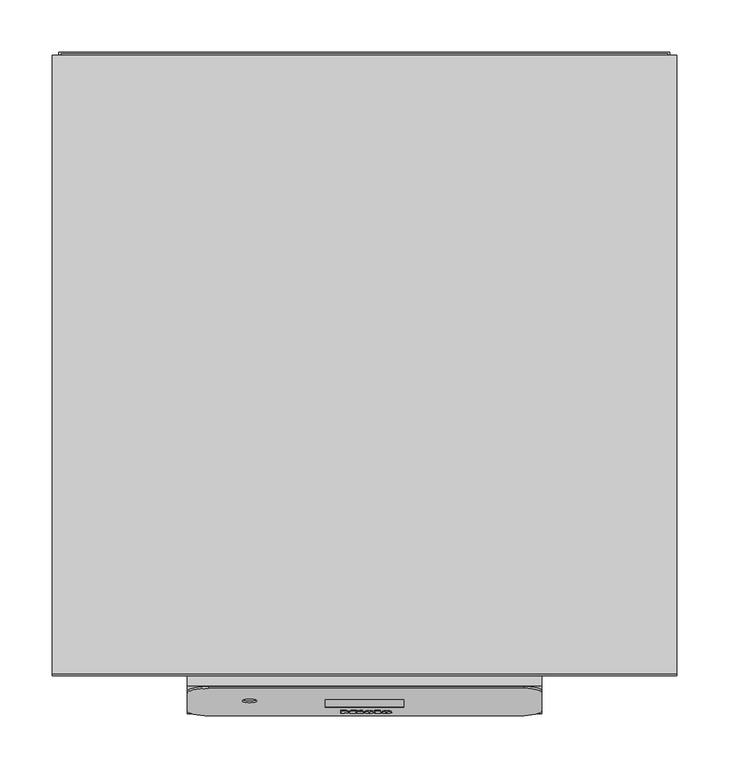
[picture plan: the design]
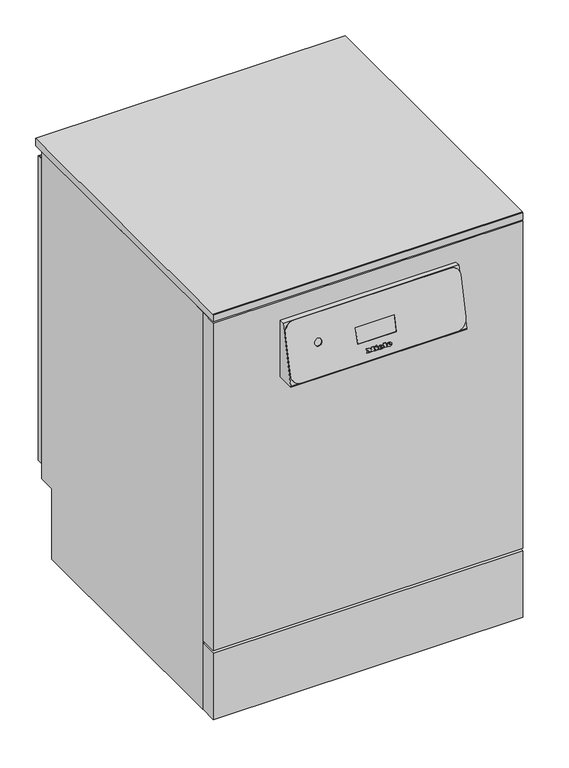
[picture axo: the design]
"""IFC4 building model written with IfcOpenShell, lengths in millimetres: proxy geometry."""

from ifc_helpers import new_model, si_unit, point, frame, frame_2d, origin, origin_with_axes, place, context, project, spatial, polyline, circle_curve, ellipse_curve, trimmed, segment, composite_curve, outline, extrude, faceted_brep, source, transform, mapped, element, save
from ifc_brep_helpers import plane_surface, cylinder_surface, revolved_surface, extruded_surface, advanced_brep


def specialty_equipment_f63f0287(model_context):
    return source(origin(), model_context, "Body", "SolidModel", [
        advanced_brep(
        [(20.656, -35.3539089, 679.552071), (20.656, -35.1721485, 680.339362), (26.008, -35.1721485, 680.339362), (16.696, -35.1721485, 680.339362), (18.896, -35.7804161, 677.7046654), (25.872, -35.3539089, 679.552071), (23.456, -35.3539089, 679.552071), (21.552, -35.5554651, 678.6790354), (20.656, -34.9417986, 681.337117), (20.656, -34.7456413, 682.1867677), (22.024, -34.7456413, 682.1867677), (22.024, -34.9417986, 681.337117), (20.656, -34.3795388, 679.3271199), (21.552, -34.581095, 678.4540844), (23.456, -34.3795388, 679.3271199), (25.872, -34.3795388, 679.3271199), (18.896, -34.806046, 677.4797143), (16.696, -34.1977784, 680.114411), (26.008, -34.1977784, 680.114411), (20.656, -34.1977784, 680.114411), (20.656, -33.9674285, 681.1121659), (22.024, -33.9674285, 681.1121659), (22.024, -33.7712712, 681.9618166), (20.656, -33.7712712, 681.9618166)],
        [
            (0, 1),
            (1, 2),
            (2, 3, ellipse_curve(frame((21.352, -35.1721485, 680.339362), z_axis=(0.0, -0.9743700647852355, 0.22495105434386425), x_axis=(-1.0, 0.0, 0.0)), 4.656, 3.848)),
            (3, 4, circle_curve(frame((19.7920436, -35.1109618, 680.6043907), z_axis=(0.0, -0.9743700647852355, 0.22495105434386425), x_axis=(0.0, -0.22495105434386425, -0.9743700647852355)), 3.1079688)),
            (4, 5, circle_curve(frame((21.2587936, -34.6358651, 682.6622603), z_axis=(0.0, -0.9743700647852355, 0.22495105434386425), x_axis=(0.0, -0.22495105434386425, -0.9743700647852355)), 5.6098607)),
            (5, 6),
            (6, 7, circle_curve(frame((21.9430588, -35.1865453, 680.2770023), z_axis=(0.0, 0.9743700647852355, -0.22495105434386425), x_axis=(0.0, -0.22495105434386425, -0.9743700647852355)), 1.6859795)),
            (7, 0, circle_curve(frame((21.552, -35.3539089, 679.552071), z_axis=(0.0, 0.9743700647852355, -0.22495105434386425), x_axis=(0.0, -0.22495105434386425, -0.9743700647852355)), 0.896)),
            (8, 9),
            (9, 10, circle_curve(frame((21.34, -34.7456413, 682.1867677), z_axis=(0.0, 0.9743700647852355, -0.22495105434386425), x_axis=(0.0, -0.22495105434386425, -0.9743700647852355)), 0.684)),
            (10, 11),
            (11, 8),
            (12, 13, circle_curve(frame((21.552, -34.3795388, 679.3271199), z_axis=(0.0, -0.9743700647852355, 0.22495105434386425), x_axis=(0.0, -0.22495105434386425, -0.9743700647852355)), 0.896)),
            (13, 14, circle_curve(frame((21.9430588, -34.2121753, 680.0520513), z_axis=(0.0, -0.9743700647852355, 0.22495105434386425), x_axis=(0.0, -0.22495105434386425, -0.9743700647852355)), 1.6859795)),
            (14, 15),
            (15, 16, circle_curve(frame((21.2587936, -33.6614951, 682.4373092), z_axis=(0.0, 0.9743700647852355, -0.22495105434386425), x_axis=(0.0, -0.22495105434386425, -0.9743700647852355)), 5.6098607)),
            (16, 17, circle_curve(frame((19.7920436, -34.1365917, 680.3794396), z_axis=(0.0, 0.9743700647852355, -0.22495105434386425), x_axis=(0.0, -0.22495105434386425, -0.9743700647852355)), 3.1079688)),
            (17, 18, ellipse_curve(frame((21.352, -34.1977784, 680.114411), z_axis=(0.0, 0.9743700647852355, -0.22495105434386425), x_axis=(-1.0, 0.0, 0.0)), 4.656, 3.848)),
            (18, 19),
            (19, 12),
            (20, 21),
            (21, 22),
            (22, 23, circle_curve(frame((21.34, -33.7712712, 681.9618166), z_axis=(0.0, -0.9743700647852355, 0.22495105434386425), x_axis=(0.0, -0.22495105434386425, -0.9743700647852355)), 0.684)),
            (23, 20),
            (0, 12),
            (19, 1),
            (18, 2),
            (5, 15),
            (14, 6),
            (17, 3),
            (13, 7),
            (16, 4),
            (8, 20),
            (23, 9),
            (22, 10),
            (21, 11),
        ],
        [
            plane_surface(frame((20.656, -35.1721485, 680.339362), z_axis=(0.0, -0.9743700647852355, 0.22495105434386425), x_axis=(0.0, 0.22495105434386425, 0.9743700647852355))),
            plane_surface(frame((20.656, -34.1977784, 680.114411), z_axis=(0.0, 0.9743700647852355, -0.22495105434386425), x_axis=(0.0, -0.22495105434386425, -0.9743700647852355))),
            plane_surface(frame((20.656, -35.3539089, 679.552071), z_axis=(1.0, 0.0, 0.0), x_axis=(0.0, 0.9743700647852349, -0.22495105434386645))),
            plane_surface(frame((20.656, -35.1721485, 680.339362), z_axis=(0.0, -0.22495105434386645, -0.9743700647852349), x_axis=(0.0, 0.9743700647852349, -0.22495105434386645))),
            plane_surface(frame((25.872, -35.3539089, 679.552071), z_axis=(0.0, 0.22495105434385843, 0.9743700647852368), x_axis=(0.0, 0.9743700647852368, -0.22495105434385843))),
            extruded_surface(trimmed(ellipse_curve(frame((21.352, -33.2234083, 679.8894599), z_axis=(0.0, -0.9743700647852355, 0.22495105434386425), x_axis=(-1.0, 0.0, 0.0)), 4.656, 3.848), [point((26.008, -33.2234083, 679.8894599))], [point((16.696, -33.2234083, 679.8894599))], True, "CARTESIAN"), (0.0, -0.9743700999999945, 0.2249510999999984), 1.0000000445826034),
            revolved_surface(polyline([(21.9430588, -34.59143807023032, 678.4092833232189), (21.9430588, -35.56580822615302, 678.6342343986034)]), (21.9430588, -34.2121753, 680.0520513), (0.0, 0.9743700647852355, -0.22495105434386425)),
            revolved_surface(polyline([(21.552, -34.581094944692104, 678.4540843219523), (21.552, -35.5554651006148, 678.679035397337)]), (21.552, -34.3795388, 679.3271199), (0.0, 0.9743700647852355, -0.22495105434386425)),
            cylinder_surface(frame((19.7920436, -34.1365917, 680.3794396), z_axis=(0.0, -0.9743700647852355, 0.22495105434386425), x_axis=(0.0, -0.22495105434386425, -0.9743700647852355)), 3.1079688),
            cylinder_surface(frame((21.2587936, -33.6614951, 682.4373092), z_axis=(0.0, -0.9743700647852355, 0.22495105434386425), x_axis=(0.0, -0.22495105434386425, -0.9743700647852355)), 5.6098607),
            plane_surface(frame((20.656, -34.9417986, 681.337117), z_axis=(1.0, 0.0, 0.0), x_axis=(0.0, 0.9743700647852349, -0.22495105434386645))),
            revolved_surface(polyline([(21.34, -33.925137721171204, 681.2953474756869), (21.34, -34.8995078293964, 681.5202985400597)]), (21.34, -33.7712712, 681.9618166), (0.0, 0.9743700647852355, -0.22495105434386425)),
            plane_surface(frame((22.024, -34.7456413, 682.1867677), z_axis=(-1.0, 0.0, 0.0), x_axis=(0.0, 0.9743700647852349, -0.22495105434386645))),
            plane_surface(frame((22.024, -34.9417986, 681.337117), z_axis=(0.0, 0.22495105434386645, 0.9743700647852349), x_axis=(0.0, 0.9743700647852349, -0.22495105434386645))),
        ],
        [
            (0, [[1, 2, 3, 4, 5, 6, 7, 8], [9, 10, 11, 12]]),
            (1, [[13, 14, 15, 16, 17, 18, 19, 20], [21, 22, 23, 24]]),
            (2, [[-1, 25, -20, 26]]),
            (3, [[-2, -26, -19, 27]]),
            (4, [[-6, 28, -15, 29]]),
            (5, [[-3, -27, -18, 30]]),
            (6, [[-7, -29, -14, 31]]),
            (7, [[-8, -31, -13, -25]]),
            (8, [[-4, -30, -17, 32]]),
            (9, [[-5, -32, -16, -28]]),
            (10, [[-9, 33, -24, 34]]),
            (11, [[-10, -34, -23, 35]]),
            (12, [[-11, -35, -22, 36]]),
            (13, [[-12, -36, -21, -33]]),
        ],
    ),
        advanced_brep(
        [(3.96, -35.3539089, 679.552071), (3.96, -35.1721485, 680.339362), (9.312, -35.1721485, 680.339362), (0.0, -35.1721485, 680.339362), (2.2, -35.7804161, 677.7046654), (9.176, -35.3539089, 679.552071), (6.76, -35.3539089, 679.552071), (4.856, -35.5554651, 678.6790354), (3.96, -34.9417986, 681.337117), (3.96, -34.7456413, 682.1867677), (5.328, -34.7456413, 682.1867677), (5.328, -34.9417986, 681.337117), (3.96, -34.3795388, 679.3271199), (4.856, -34.581095, 678.4540844), (6.76, -34.3795388, 679.3271199), (9.176, -34.3795388, 679.3271199), (2.2, -34.806046, 677.4797143), (0.0, -34.1977784, 680.114411), (9.312, -34.1977784, 680.114411), (3.96, -34.1977784, 680.114411), (3.96, -33.9674285, 681.1121659), (5.328, -33.9674285, 681.1121659), (5.328, -33.7712712, 681.9618166), (3.96, -33.7712712, 681.9618166)],
        [
            (0, 1),
            (1, 2),
            (2, 3, ellipse_curve(frame((4.656, -35.1721485, 680.339362), z_axis=(0.0, -0.9743700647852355, 0.22495105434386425), x_axis=(-1.0, 0.0, 0.0)), 4.656, 3.848)),
            (3, 4, circle_curve(frame((3.0960436, -35.1109618, 680.6043907), z_axis=(0.0, -0.9743700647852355, 0.22495105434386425), x_axis=(0.0, -0.22495105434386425, -0.9743700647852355)), 3.1079688)),
            (4, 5, circle_curve(frame((4.5627936, -34.6358651, 682.6622603), z_axis=(0.0, -0.9743700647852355, 0.22495105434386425), x_axis=(0.0, -0.22495105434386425, -0.9743700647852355)), 5.6098607)),
            (5, 6),
            (6, 7, circle_curve(frame((5.2470588, -35.1865453, 680.2770023), z_axis=(0.0, 0.9743700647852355, -0.22495105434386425), x_axis=(0.0, -0.22495105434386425, -0.9743700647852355)), 1.6859795)),
            (7, 0, circle_curve(frame((4.856, -35.3539089, 679.552071), z_axis=(0.0, 0.9743700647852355, -0.22495105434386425), x_axis=(0.0, -0.22495105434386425, -0.9743700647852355)), 0.896)),
            (8, 9),
            (9, 10, circle_curve(frame((4.644, -34.7456413, 682.1867677), z_axis=(0.0, 0.9743700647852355, -0.22495105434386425), x_axis=(0.0, -0.22495105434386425, -0.9743700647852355)), 0.684)),
            (10, 11),
            (11, 8),
            (12, 13, circle_curve(frame((4.856, -34.3795388, 679.3271199), z_axis=(0.0, -0.9743700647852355, 0.22495105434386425), x_axis=(0.0, -0.22495105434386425, -0.9743700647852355)), 0.896)),
            (13, 14, circle_curve(frame((5.2470588, -34.2121753, 680.0520513), z_axis=(0.0, -0.9743700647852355, 0.22495105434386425), x_axis=(0.0, -0.22495105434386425, -0.9743700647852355)), 1.6859795)),
            (14, 15),
            (15, 16, circle_curve(frame((4.5627936, -33.6614951, 682.4373092), z_axis=(0.0, 0.9743700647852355, -0.22495105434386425), x_axis=(0.0, -0.22495105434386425, -0.9743700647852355)), 5.6098607)),
            (16, 17, circle_curve(frame((3.0960436, -34.1365917, 680.3794396), z_axis=(0.0, 0.9743700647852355, -0.22495105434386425), x_axis=(0.0, -0.22495105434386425, -0.9743700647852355)), 3.1079688)),
            (17, 18, ellipse_curve(frame((4.656, -34.1977784, 680.114411), z_axis=(0.0, 0.9743700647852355, -0.22495105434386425), x_axis=(-1.0, 0.0, 0.0)), 4.656, 3.848)),
            (18, 19),
            (19, 12),
            (20, 21),
            (21, 22),
            (22, 23, circle_curve(frame((4.644, -33.7712712, 681.9618166), z_axis=(0.0, -0.9743700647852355, 0.22495105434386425), x_axis=(0.0, -0.22495105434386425, -0.9743700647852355)), 0.684)),
            (23, 20),
            (0, 12),
            (19, 1),
            (18, 2),
            (5, 15),
            (14, 6),
            (17, 3),
            (13, 7),
            (16, 4),
            (8, 20),
            (23, 9),
            (22, 10),
            (21, 11),
        ],
        [
            plane_surface(frame((3.96, -35.1721485, 680.339362), z_axis=(0.0, -0.9743700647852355, 0.22495105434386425), x_axis=(0.0, 0.22495105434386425, 0.9743700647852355))),
            plane_surface(frame((3.96, -34.1977784, 680.114411), z_axis=(0.0, 0.9743700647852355, -0.22495105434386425), x_axis=(0.0, -0.22495105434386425, -0.9743700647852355))),
            plane_surface(frame((3.96, -35.3539089, 679.552071), z_axis=(1.0, 0.0, 0.0), x_axis=(0.0, 0.9743700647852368, -0.22495105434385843))),
            plane_surface(frame((3.96, -35.1721485, 680.339362), z_axis=(0.0, -0.22495105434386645, -0.9743700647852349), x_axis=(0.0, 0.9743700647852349, -0.22495105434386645))),
            plane_surface(frame((9.176, -35.3539089, 679.552071), z_axis=(0.0, 0.22495105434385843, 0.9743700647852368), x_axis=(0.0, 0.9743700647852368, -0.22495105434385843))),
            extruded_surface(trimmed(ellipse_curve(frame((4.656, -33.2234083, 679.8894599), z_axis=(0.0, -0.9743700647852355, 0.22495105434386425), x_axis=(-1.0, 0.0, 0.0)), 4.656, 3.848), [point((9.312, -33.2234083, 679.8894599))], [point((0.0, -33.2234083, 679.8894599))], True, "CARTESIAN"), (0.0, -0.9743700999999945, 0.2249510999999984), 1.0000000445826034),
            revolved_surface(polyline([(5.2470588, -34.59143807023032, 678.4092833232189), (5.2470588, -35.56580822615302, 678.6342343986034)]), (5.2470588, -34.2121753, 680.0520513), (0.0, 0.9743700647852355, -0.22495105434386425)),
            revolved_surface(polyline([(4.856, -34.581094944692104, 678.4540843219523), (4.856, -35.5554651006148, 678.679035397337)]), (4.856, -34.3795388, 679.3271199), (0.0, 0.9743700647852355, -0.22495105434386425)),
            cylinder_surface(frame((3.0960436, -34.1365917, 680.3794396), z_axis=(0.0, -0.9743700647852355, 0.22495105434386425), x_axis=(0.0, -0.22495105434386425, -0.9743700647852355)), 3.1079688),
            cylinder_surface(frame((4.5627936, -33.6614951, 682.4373092), z_axis=(0.0, -0.9743700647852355, 0.22495105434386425), x_axis=(0.0, -0.22495105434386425, -0.9743700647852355)), 5.6098607),
            plane_surface(frame((3.96, -34.9417986, 681.337117), z_axis=(1.0, 0.0, 0.0), x_axis=(0.0, 0.9743700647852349, -0.22495105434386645))),
            revolved_surface(polyline([(4.644, -33.925137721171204, 681.2953474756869), (4.644, -34.8995078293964, 681.5202985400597)]), (4.644, -33.7712712, 681.9618166), (0.0, 0.9743700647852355, -0.22495105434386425)),
            plane_surface(frame((5.328, -34.7456413, 682.1867677), z_axis=(-1.0, 0.0, 0.0), x_axis=(0.0, 0.9743700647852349, -0.22495105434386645))),
            plane_surface(frame((5.328, -34.9417986, 681.337117), z_axis=(0.0, 0.22495105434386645, 0.9743700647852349), x_axis=(0.0, 0.9743700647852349, -0.22495105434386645))),
        ],
        [
            (0, [[1, 2, 3, 4, 5, 6, 7, 8], [9, 10, 11, 12]]),
            (1, [[13, 14, 15, 16, 17, 18, 19, 20], [21, 22, 23, 24]]),
            (2, [[-1, 25, -20, 26]]),
            (3, [[-2, -26, -19, 27]]),
            (4, [[-6, 28, -15, 29]]),
            (5, [[-3, -27, -18, 30]]),
            (6, [[-7, -29, -14, 31]]),
            (7, [[-8, -31, -13, -25]]),
            (8, [[-4, -30, -17, 32]]),
            (9, [[-5, -32, -16, -28]]),
            (10, [[-9, 33, -24, 34]]),
            (11, [[-10, -34, -23, 35]]),
            (12, [[-11, -35, -22, 36]]),
            (13, [[-12, -36, -21, -33]]),
        ],
    ),
        extrude(outline(polyline([(0.0, 0.0), (-0.0109087, -2.9993294), (-1.4390415, -2.9920868), (-1.4315307, 0.0), (0.0, 0.0)])), frame((-4.784, -33.1126145, 684.8147722), z_axis=(0.0, -0.9743700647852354, 0.22495105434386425), x_axis=(-0.42472021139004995, 0.20365373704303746, 0.8821212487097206)), (0.0, 0.0, 1.0), 1.0),
        extrude(outline(polyline([(-0.4933908, 2.4141097), (-2.7800844, -2.4601583), (-7.0459742, -0.4588767), (-7.4401146, -1.2990179), (-8.6568709, -0.728194), (-5.9760369, 4.9862153), (-4.7592806, 4.4153913), (-5.1636142, 3.5535222), (-2.1941494, 2.16044), (-1.7898157, 3.022309), (-0.4933908, 2.4141097)])), frame((-4.784, -33.1126145, 684.8147722), z_axis=(0.0, -0.9743700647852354, 0.22495105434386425), x_axis=(-0.42472021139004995, 0.20365373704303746, 0.8821212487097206)), (0.0, 0.0, 1.0), 1.0),
        extrude(outline(polyline([(0.0, 0.0), (0.0, -1.3039999), (-5.504, -1.3039999), (-5.504, 5.352), (-6.488, 5.352), (-6.488, 6.696), (0.0, 6.696), (0.0, 5.352), (-0.96, 5.352), (-0.96, 0.0), (0.0, 0.0)])), frame((9.76, -33.2997738, 684.0040963), z_axis=(0.0, -0.9743700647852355, 0.22495105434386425), x_axis=(-1.0, 0.0, 0.0)), (0.0, 0.0, 1.0), 1.0),
        extrude(outline(polyline([(0.0, 0.0), (0.0, -1.3039999), (-5.576, -1.3039999), (-7.92, 1.6960001), (-10.256, -1.3039999), (-15.128, -1.3039999), (-15.128, 0.0), (-14.112, 0.0), (-14.112, 5.352), (-15.128, 5.352), (-15.128, 6.696), (-8.744, 6.696), (-8.744, 5.352), (-9.728, 5.352), (-9.728, 1.8807777), (-6.136, 6.696), (-2.56, 1.9488752), (-2.56, 5.352), (-3.52, 5.352), (-3.52, 6.696), (0.0, 6.696), (0.0, 5.352), (-0.968, 5.352), (-0.968, 0.0), (0.0, 0.0)])), frame((-22.704, -33.2997738, 684.0040963), z_axis=(0.0, -0.9743700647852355, 0.22495105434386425), x_axis=(-1.0, 0.0, 0.0)), (0.0, 0.0, 1.0), 1.0),
        extrude(outline(polyline([(1.7745866, 832.3), (594.2, 832.3), (594.2, 817.0), (0.2, 817.0), (0.2, 830.7254134), (1.7745866, 832.3)])), frame((-299.0, 0.0, 0.0), z_axis=(1.0, 0.0, 0.0), x_axis=(0.0, 1.0, 0.0)), (0.0, 0.0, 1.0), 598.0),
        extrude(outline(polyline([(-0.1038681, 775.5857792), (-0.1038681, 660.0), (-36.1981904, 660.0), (-36.1981904, 662.5588517), (-10.1038681, 775.5857792), (-0.1038681, 775.5857792)])), frame((-169.8831565, 0.0, 0.0), z_axis=(1.0, 0.0, 0.0), x_axis=(0.0, 1.0, 0.0)), (0.0, 0.0, 1.0), 339.766313),
        extrude(outline(polyline([(299.0, 34.0), (299.0, 0.0), (-299.0, 0.0), (-299.0, 34.0), (299.0, 34.0)])), frame((0.0, 0.0, 4.5), z_axis=(0.0, 0.0, 1.0), x_axis=(1.0, 0.0, 0.0)), (0.0, 0.0, 1.0), 135.5),
        extrude(outline(polyline([(299.0, 34.0), (299.0, 0.0), (-299.0, 0.0), (-299.0, 34.0), (299.0, 34.0)])), frame((0.0, 0.0, 145.0), z_axis=(0.0, 0.0, 1.0), x_axis=(1.0, 0.0, 0.0)), (0.0, 0.0, 1.0), 670.0),
        advanced_brep(
        [(153.3281651, -12.0526082, 776.0356813), (-148.8831565, -12.0526082, 776.0356813), (-169.8831565, -16.7765804, 755.57391), (-169.8831565, -33.4229584, 683.4705252), (-148.8831565, -38.1469305, 663.0087538), (148.8831565, -38.1469305, 663.0087538), (169.8831565, -33.4229584, 683.4705252), (169.8831565, -15.776671, 759.9049933), (-102.8831565, -24.0088923, 724.2473253), (-116.8831565, -24.0088923, 724.2473253), (37.5, -23.1425191, 728.0), (37.5, -30.0685648, 698.0), (-37.5, -30.0685648, 698.0), (-37.5, -23.1425191, 728.0), (148.8831565, -36.1981904, 662.5588517), (169.8831565, -31.4742182, 683.0206231), (169.8831565, -13.8279308, 759.4550912), (153.3281651, -10.1038681, 775.5857792), (-148.8831565, -36.1981904, 662.5588517), (-169.8831565, -31.4742182, 683.0206231), (-169.8831565, -14.8278402, 755.1240079), (-148.8831565, -10.1038681, 775.5857792), (37.5, -28.0159566, 698.0), (37.5, -21.0899109, 728.0), (-37.5, -21.0899109, 728.0), (-37.5, -28.0159566, 698.0), (-116.8831565, -22.4281396, 723.8823798), (-102.8831565, -22.4281396, 723.8823798)],
        [
            (0, 1),
            (1, 2, circle_curve(frame((-148.8831565, -16.7765804, 755.57391), z_axis=(0.0, -0.9743700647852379, 0.22495105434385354), x_axis=(1.0, 0.0, 0.0)), 21.0)),
            (2, 3),
            (3, 4, circle_curve(frame((-148.8831565, -33.4229584, 683.4705252), z_axis=(0.0, -0.9743700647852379, 0.22495105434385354), x_axis=(1.0, 0.0, 0.0)), 21.0)),
            (4, 5),
            (5, 6, circle_curve(frame((148.8831565, -33.4229584, 683.4705252), z_axis=(0.0, -0.9743700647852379, 0.22495105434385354), x_axis=(1.0, 0.0, 0.0)), 21.0)),
            (6, 7),
            (7, 0, circle_curve(frame((153.3281651, -15.776671, 759.9049933), z_axis=(0.0, -0.9743700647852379, 0.22495105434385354), x_axis=(1.0, 0.0, 0.0)), 16.5549913)),
            (8, 9, circle_curve(frame((-109.8831565, -24.0088923, 724.2473253), z_axis=(0.0, 0.9743700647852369, -0.22495105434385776), x_axis=(1.0, 0.0, 0.0)), 7.0)),
            (9, 8, circle_curve(frame((-109.8831565, -24.0088923, 724.2473253), z_axis=(0.0, 0.9743700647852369, -0.22495105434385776), x_axis=(1.0, 0.0, 0.0)), 7.0)),
            (10, 11),
            (11, 12),
            (12, 13),
            (13, 10),
            (5, 14),
            (14, 15, circle_curve(frame((148.8831565, -31.4742182, 683.0206231), z_axis=(0.0, -0.9743700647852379, 0.22495105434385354), x_axis=(1.0, 0.0, 0.0)), 21.0)),
            (15, 6),
            (15, 16),
            (16, 7),
            (16, 17, circle_curve(frame((153.3281651, -13.8279308, 759.4550912), z_axis=(0.0, -0.9743700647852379, 0.22495105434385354), x_axis=(1.0, 0.0, 0.0)), 16.5549913)),
            (17, 0),
            (14, 18),
            (18, 19, circle_curve(frame((-148.8831565, -31.4742182, 683.0206231), z_axis=(0.0, 0.9743700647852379, -0.22495105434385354), x_axis=(1.0, 0.0, 0.0)), 21.0)),
            (19, 20),
            (20, 21, circle_curve(frame((-148.8831565, -14.8278402, 755.1240079), z_axis=(0.0, 0.9743700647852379, -0.22495105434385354), x_axis=(1.0, 0.0, 0.0)), 21.0)),
            (21, 17),
            (22, 23),
            (23, 24),
            (24, 25),
            (25, 22),
            (21, 1),
            (20, 2),
            (19, 3),
            (18, 4),
            (26, 27, circle_curve(frame((-109.8831565, -22.4281396, 723.8823798), z_axis=(0.0, -0.9743700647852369, 0.22495105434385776), x_axis=(1.0, 0.0, 0.0)), 7.0)),
            (27, 26, circle_curve(frame((-109.8831565, -22.4281396, 723.8823798), z_axis=(0.0, -0.9743700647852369, 0.22495105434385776), x_axis=(1.0, 0.0, 0.0)), 7.0)),
            (26, 9),
            (8, 27),
            (11, 22),
            (25, 12),
            (23, 10),
            (13, 24),
        ],
        [
            plane_surface(frame((-166.8819453, -12.0526082, 776.0356813), z_axis=(0.0, -0.9743700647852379, 0.22495105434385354), x_axis=(-1.0, 0.0, 0.0))),
            cylinder_surface(frame((148.8831565, -31.4742182, 683.0206231), z_axis=(0.0, -0.9743700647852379, 0.22495105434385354), x_axis=(1.0, 0.0, 0.0)), 21.0),
            plane_surface(frame((169.8831565, -33.4229584, 683.4705252), z_axis=(1.0000000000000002, 0.0, 0.0), x_axis=(0.0, 0.9743700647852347, -0.22495105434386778))),
            cylinder_surface(frame((153.3281651, -13.8279308, 759.4550912), z_axis=(0.0, -0.9743700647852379, 0.22495105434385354), x_axis=(1.0, 0.0, 0.0)), 16.5549913),
            plane_surface(frame((-166.8819453, -10.1038681, 775.5857792), z_axis=(0.0, 0.9743700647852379, -0.22495105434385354), x_axis=(1.0, 0.0, 0.0))),
            plane_surface(frame((153.3281651, -12.0526082, 776.0356813), z_axis=(0.0, 0.22495105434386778, 0.9743700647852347), x_axis=(0.0, 0.9743700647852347, -0.22495105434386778))),
            cylinder_surface(frame((-148.8831565, -14.8278402, 755.1240079), z_axis=(0.0, -0.9743700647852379, 0.22495105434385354), x_axis=(1.0, 0.0, 0.0)), 21.0),
            plane_surface(frame((-169.8831565, -16.7765804, 755.57391), z_axis=(-1.0, 0.0, 0.0), x_axis=(0.0, 0.9743700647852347, -0.22495105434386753))),
            cylinder_surface(frame((-148.8831565, -31.4742182, 683.0206231), z_axis=(0.0, -0.9743700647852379, 0.22495105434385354), x_axis=(1.0, 0.0, 0.0)), 21.0),
            plane_surface(frame((-148.8831565, -38.1469305, 663.0087538), z_axis=(0.0, -0.22495105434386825, -0.9743700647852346), x_axis=(0.0, 0.9743700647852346, -0.22495105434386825))),
            plane_surface(frame((-102.8831565, -22.4281396, 723.8823798), z_axis=(0.0, -0.9743700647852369, 0.2249510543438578), x_axis=(0.0, -0.2249510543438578, -0.9743700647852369))),
            revolved_surface(polyline([(-102.8831565, -24.008892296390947, 724.2473253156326), (-102.8831565, -22.4281396, 723.8823798)]), (-109.8831565, -22.4281396, 723.8823798), (0.0, -0.9743700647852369, 0.22495105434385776)),
            plane_surface(frame((37.5, -30.0685648, 698.0), z_axis=(0.0, 0.0, 1.0), x_axis=(-1.0, 0.0, 0.0))),
            plane_surface(frame((37.5, -21.0899109, 728.0), z_axis=(0.0, 0.0, -1.0), x_axis=(-1.0, 0.0, 0.0))),
            plane_surface(frame((37.5, -23.1425191, 728.0), z_axis=(-1.0000000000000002, 0.0, 0.0), x_axis=(0.0, -0.22495105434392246, -0.974370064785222))),
            plane_surface(frame((-37.5, -23.1425191, 728.0), z_axis=(1.0000000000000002, 0.0, 0.0), x_axis=(0.0, 0.22495105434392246, 0.974370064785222))),
        ],
        [
            (0, [[1, 2, 3, 4, 5, 6, 7, 8], [9, 10], [11, 12, 13, 14]]),
            (1, [[-6, 15, 16, 17]]),
            (2, [[-7, -17, 18, 19]]),
            (3, [[-8, -19, 20, 21]]),
            (4, [[-20, -18, -16, 22, 23, 24, 25, 26], [27, 28, 29, 30]]),
            (5, [[-1, -21, -26, 31]]),
            (6, [[-2, -31, -25, 32]]),
            (7, [[-3, -32, -24, 33]]),
            (8, [[-4, -33, -23, 34]]),
            (9, [[-5, -34, -22, -15]]),
            (10, [[35, 36]]),
            (11, [[-35, 37, -9, 38]]),
            (11, [[-36, -38, -10, -37]]),
            (12, [[39, -30, 40, -12]]),
            (13, [[41, -14, 42, -28]]),
            (14, [[-41, -27, -39, -11]]),
            (15, [[-40, -29, -42, -13]]),
        ],
    ),
        extrude(outline(polyline([(-23.1425191, 728.0), (-21.0899109, 728.0), (-28.0159566, 698.0), (-30.0685648, 698.0), (-23.1425191, 728.0)])), frame((-37.5, 0.0, 0.0), z_axis=(1.0, 0.0, 0.0), x_axis=(0.0, 1.0, 0.0)), (0.0, 0.0, 1.0), 75.0),
        extrude(outline(polyline([(35.0, 817.0), (575.0, 817.0), (575.0, 148.0), (541.0, 148.0), (541.0, 4.2000122), (35.0, 4.2000122), (35.0, 817.0)])), frame((-299.0, 0.0, 0.0), z_axis=(1.0, 0.0, 0.0), x_axis=(0.0, 1.0, 0.0)), (0.0, 0.0, 1.0), 598.0),
        extrude(outline(polyline([(-172.0947306, 541.0), (-252.9150967, 541.0), (-252.9150967, 546.8796322), (-172.0947306, 546.8796322), (-172.0947306, 541.0)])), frame((0.0, 0.0, 83.2113443), z_axis=(0.0, 0.0, 1.0), x_axis=(1.0, 0.0, 0.0)), (0.0, 0.0, 1.0), 9.5402229),
        extrude(outline(polyline([(-172.0947306, 541.0), (-252.9150967, 541.0), (-252.9150967, 546.8796322), (-172.0947306, 546.8796322), (-172.0947306, 541.0)])), frame((0.0, 0.0, 67.2113431), z_axis=(0.0, 0.0, 1.0), x_axis=(1.0, 0.0, 0.0)), (0.0, 0.0, 1.0), 9.5826234),
        extrude(outline(polyline([(-172.0947306, 541.0), (-252.9150967, 541.0), (-252.9150967, 546.8796322), (-172.0947306, 546.8796322), (-172.0947306, 541.0)])), frame((0.0, 0.0, 49.1113767), z_axis=(0.0, 0.0, 1.0), x_axis=(1.0, 0.0, 0.0)), (0.0, 0.0, 1.0), 11.5700235),
        faceted_brep([(292.4999939, 597.3069992, 792.0057337), (-292.5000061, 597.3069992, 792.0057337), (-292.5000061, 575.0, 792.0057337), (-291.0000061, 575.0, 792.0057337), (-291.0000061, 596.3069992, 792.0057337), (290.9999949, 596.3069992, 792.0057337), (290.9999949, 575.0, 792.0057337), (292.4999939, 575.0, 792.0057337), (292.4999939, 597.3069992, 170.291519), (292.4999939, 575.0, 170.291519), (290.9999949, 575.0, 170.291519), (290.9999949, 596.3069992, 170.291519), (-291.0000061, 596.3069992, 170.291519), (-291.0000061, 575.0, 170.291519), (-292.5000061, 575.0, 170.291519), (-292.5000061, 597.3069992, 170.291519), (-200.000102, 597.3069992, 319.6113699), (-200.000102, 597.3069992, 244.365213), (-125.000102, 597.3069992, 244.365213), (-125.000102, 597.3069992, 319.6113699), (-200.000102, 596.3069992, 244.365213), (-200.000102, 596.3069992, 319.6113699), (-125.000102, 596.3069992, 319.6113699), (-125.000102, 596.3069992, 244.365213)], [[[0, 1, 2, 3, 4, 5, 6, 7]], [[8, 9, 10, 11, 12, 13, 14, 15]], [[1, 0, 8, 15], [16, 17, 18, 19]], [[2, 1, 15, 14]], [[3, 2, 14, 13]], [[4, 3, 13, 12]], [[5, 4, 12, 11], [20, 21, 22, 23]], [[6, 5, 11, 10]], [[7, 6, 10, 9]], [[0, 7, 9, 8]], [[20, 17, 16, 21]], [[17, 20, 23, 18]], [[18, 23, 22, 19]], [[21, 16, 19, 22]]]),
        extrude(outline(polyline([(70.6242327, 186.565003), (80.6698637, 186.565003), (80.6698637, 179.3447057), (79.4141598, 179.3447057), (79.4141598, 185.3092991), (76.4318631, 185.3092991), (76.4318631, 179.6586317), (75.1761592, 179.6586317), (75.1761592, 185.3092991), (71.8799366, 185.3092991), (71.8799366, 179.1877427), (70.6242327, 179.1877427), (70.6242327, 186.565003)])), frame((0.0, 571.0, 0.0), z_axis=(0.0, 1.0, 0.0), x_axis=(0.0, 0.0, 1.0)), (0.0, 0.0, 1.0), 1.0),
        extrude(outline(polyline([(70.6242327, 177.3041869), (80.6698637, 177.3041869), (80.6698637, 176.048483), (71.8799366, 176.048483), (71.8799366, 171.0256675), (70.6242327, 171.0256675), (70.6242327, 177.3041869)])), frame((0.0, 571.0, 0.0), z_axis=(0.0, 1.0, 0.0), x_axis=(0.0, 0.0, 1.0)), (0.0, 0.0, 1.0), 1.0),
        extrude(outline(polyline([(46.0, 96.7862239), (56.045631, 92.7763102), (56.045631, 91.7069998), (46.0, 87.6970861), (46.0, 89.0239138), (49.1392597, 90.1741582), (49.1392597, 94.3116044), (46.0, 95.4593962), (46.0, 96.7862239)]), holes=[polyline([(50.3949636, 93.8505256), (50.3949636, 90.6327844), (52.864678, 91.5377741), (54.7899271, 92.241655), (53.0805021, 92.8670544), (50.3949636, 93.8505256)])]), frame((0.0, 571.0, 0.0), z_axis=(0.0, 1.0, 0.0), x_axis=(0.0, 0.0, 1.0)), (0.0, 0.0, 1.0), 1.0),
        extrude(outline(polyline([(46.0, 84.5578264), (56.045631, 87.297321), (56.045631, 86.0023764), (49.4433755, 84.4131261), (47.4053092, 83.9226168), (49.207931, 83.3977718), (56.045631, 81.406304), (56.045631, 79.539916), (51.0890343, 78.0929135), (47.4053092, 77.0162455), (49.3845144, 76.5404514), (56.045631, 74.936486), (56.045631, 73.6415413), (46.0, 76.3834885), (46.0, 77.7250315), (53.7500474, 80.1334323), (54.8316204, 80.4694312), (53.5293182, 80.8471233), (46.0, 83.0421526), (46.0, 84.5578264)])), frame((0.0, 571.0, 0.0), z_axis=(0.0, 1.0, 0.0), x_axis=(0.0, 0.0, 1.0)), (0.0, 0.0, 1.0), 1.0),
        extrude(outline(composite_curve([segment(trimmed(circle_curve(frame_2d((51.0, 85.0998392)), 8.0), [point((51.0, 77.0998392))], [point((51.0, 93.0998392))], False, "CARTESIAN"), True, "CONTINUOUS"), segment(trimmed(circle_curve(frame_2d((51.0, 85.0998392)), 8.0), [point((51.0, 93.0998392))], [point((51.0, 77.0998392))], False, "CARTESIAN"), True, "CONTINUOUS")], self_intersect=False)), frame((0.0, 541.0, 0.0), z_axis=(0.0, 1.0, 0.0), x_axis=(0.0, 0.0, 1.0)), (0.0, 0.0, 1.0), 30.0),
        extrude(outline(polyline([(94.6239875, 133.557834), (104.6696185, 136.2973286), (104.6696185, 135.002384), (98.067363, 133.4131338), (96.0292967, 132.9226244), (97.8319185, 132.3977795), (104.6696185, 130.4063116), (104.6696185, 128.5399236), (99.7130218, 127.0929211), (96.0292967, 126.0162531), (98.0085019, 125.5404591), (104.6696185, 123.9364936), (104.6696185, 122.641549), (94.6239875, 125.3834961), (94.6239875, 126.7250391), (102.3740349, 129.1334399), (103.4556079, 129.4694388), (102.1533057, 129.847131), (94.6239875, 132.0421602), (94.6239875, 133.557834)])), frame((0.0, 571.0, 0.0), z_axis=(0.0, 1.0, 0.0), x_axis=(0.0, 0.0, 1.0)), (0.0, 0.0, 1.0), 1.0),
        extrude(outline(polyline([(94.6239875, 144.6163668), (104.6696185, 144.6163668), (104.6696185, 143.3606629), (99.7522625, 143.3606629), (104.6696185, 138.210315), (104.6696185, 136.4542916), (100.53953, 140.7781313), (94.6239875, 136.2973286), (94.6239875, 137.8326228), (99.6909489, 141.6684057), (98.0771732, 143.3606629), (94.6239875, 143.3606629), (94.6239875, 144.6163668)])), frame((0.0, 571.0, 0.0), z_axis=(0.0, 1.0, 0.0), x_axis=(0.0, 0.0, 1.0)), (0.0, 0.0, 1.0), 1.0),
        extrude(outline(polyline([(118.1398187, 18.2077062), (128.1854497, 18.2077062), (128.1854497, 14.7422578), (128.0407495, 12.9494462), (127.3221533, 11.4730132), (125.6053707, 10.283528), (123.2165903, 9.888668), (121.1895605, 10.1559956), (119.7266164, 10.8427087), (118.8154953, 11.7599611), (118.311497, 12.9604827), (118.1398187, 14.5754846), (118.1398187, 18.2077062)]), holes=[polyline([(119.3955226, 16.9520023), (119.3955226, 14.7299951), (119.5770111, 13.1137669), (120.0895933, 12.1817991), (121.3367133, 11.4178309), (123.2362106, 11.1443719), (125.6151809, 11.6802533), (126.728637, 12.9837819), (126.9297459, 14.7643307), (126.9297459, 16.9520023), (119.3955226, 16.9520023)])]), frame((0.0, 571.0, 0.0), z_axis=(0.0, 1.0, 0.0), x_axis=(0.0, 0.0, 1.0)), (0.0, 0.0, 1.0), 1.0),
        extrude(outline(polyline([(121.5930044, 8.6329642), (121.5930044, 7.3772603), (120.3360742, 6.9725901), (119.5414491, 5.9842138), (119.2385596, 4.4783502), (119.4678727, 3.1662377), (120.0981772, 2.3188828), (120.940627, 2.0405188), (121.7242156, 2.2489853), (122.2944327, 3.1024715), (122.7739056, 4.930845), (123.3931736, 6.8990137), (124.3275939, 7.9670977), (125.5759401, 8.3190382), (126.9971909, 7.8837112), (128.0002825, 6.6120657), (128.3424127, 4.7505828), (127.9843409, 2.7640201), (126.9321984, 1.4396449), (125.360116, 0.9417779), (125.360116, 2.1974818), (126.6501555, 2.9087203), (127.0867088, 4.7015319), (126.6550606, 6.4992486), (125.6127283, 7.0633343), (124.7420743, 6.6635692), (124.0406459, 4.6132402), (123.4103414, 2.391233), (122.3925346, 1.1759961), (120.9725101, 0.7848149), (119.4703253, 1.2348572), (118.3740369, 2.5298019), (117.9828557, 4.4292992), (118.4046938, 6.6721531), (119.6751129, 8.0909513), (121.5930044, 8.6329642)])), frame((0.0, 571.0, 0.0), z_axis=(0.0, 1.0, 0.0), x_axis=(0.0, 0.0, 1.0)), (0.0, 0.0, 1.0), 1.0),
        extrude(outline(composite_curve([segment(trimmed(circle_curve(frame_2d((126.8499756, 10.1811127)), 2.9851521), [point((126.8499756, 7.1959606))], [point((126.8499756, 13.1662647))], False, "CARTESIAN"), True, "CONTINUOUS"), segment(trimmed(circle_curve(frame_2d((126.8499756, 10.1811127)), 2.9851521), [point((126.8499756, 13.1662647))], [point((126.8499756, 7.1959606))], False, "CARTESIAN"), True, "CONTINUOUS")], self_intersect=False)), frame((0.0, 541.0, 0.0), z_axis=(0.0, 1.0, 0.0), x_axis=(0.0, 0.0, 1.0)), (0.0, 0.0, 1.0), 30.0),
        extrude(outline(composite_curve([segment(trimmed(circle_curve(frame_2d((117.0999756, 10.1811127)), 3.0), [point((117.0999756, 7.1811127))], [point((117.0999756, 13.1811127))], False, "CARTESIAN"), True, "CONTINUOUS"), segment(trimmed(circle_curve(frame_2d((117.0999756, 10.1811127)), 3.0), [point((117.0999756, 13.1811127))], [point((117.0999756, 7.1811127))], False, "CARTESIAN"), True, "CONTINUOUS")], self_intersect=False)), frame((0.0, 541.0, 0.0), z_axis=(0.0, 1.0, 0.0), x_axis=(0.0, 0.0, 1.0)), (0.0, 0.0, 1.0), 30.0),
        extrude(outline(composite_curve([segment(trimmed(circle_curve(frame_2d((107.3499443, 10.1811127)), 3.0), [point((107.3499443, 7.1811127))], [point((107.3499443, 13.1811127))], False, "CARTESIAN"), True, "CONTINUOUS"), segment(trimmed(circle_curve(frame_2d((107.3499443, 10.1811127)), 3.0), [point((107.3499443, 13.1811127))], [point((107.3499443, 7.1811127))], False, "CARTESIAN"), True, "CONTINUOUS")], self_intersect=False)), frame((0.0, 541.0, 0.0), z_axis=(0.0, 1.0, 0.0), x_axis=(0.0, 0.0, 1.0)), (0.0, 0.0, 1.0), 30.0),
        extrude(outline(composite_curve([segment(trimmed(circle_curve(frame_2d((136.5999756, 10.1811127)), 3.0), [point((136.5999756, 7.1811127))], [point((136.5999756, 13.1811127))], False, "CARTESIAN"), True, "CONTINUOUS"), segment(trimmed(circle_curve(frame_2d((136.5999756, 10.1811127)), 3.0), [point((136.5999756, 13.1811127))], [point((136.5999756, 7.1811127))], False, "CARTESIAN"), True, "CONTINUOUS")], self_intersect=False)), frame((0.0, 541.0, 0.0), z_axis=(0.0, 1.0, 0.0), x_axis=(0.0, 0.0, 1.0)), (0.0, 0.0, 1.0), 30.0),
        extrude(outline(polyline([(99.6239875, 19.6811122), (148.0, 19.6811122), (148.0, 1.1811127), (99.6239875, 1.1811127), (99.6239875, 19.6811122)]), holes=[polyline([(100.6239875, 18.6811122), (100.6239875, 2.1811127), (147.0, 2.1811127), (147.0, 18.6811122), (100.6239875, 18.6811122)])]), frame((0.0, 541.0, 0.0), z_axis=(0.0, 1.0, 0.0), x_axis=(0.0, 0.0, 1.0)), (0.0, 0.0, 1.0), 1.0),
        extrude(outline(polyline([(41.5900269, 145.1730949), (51.6356579, 147.9125895), (51.6356579, 146.6176449), (45.0334023, 145.0283946), (42.9953361, 144.5378853), (44.7979579, 144.0130403), (51.6356579, 142.0215725), (51.6356579, 140.1551845), (46.6790611, 138.708182), (42.9953361, 137.631514), (44.9745412, 137.1557199), (51.6356579, 135.5517544), (51.6356579, 134.2568098), (41.5900269, 136.998757), (41.5900269, 138.3403), (49.3400742, 140.7487008), (50.4216473, 141.0846996), (49.119345, 141.4623918), (41.5900269, 143.6574211), (41.5900269, 145.1730949)])), frame((0.0, 571.0, 0.0), z_axis=(0.0, 1.0, 0.0), x_axis=(0.0, 0.0, 1.0)), (0.0, 0.0, 1.0), 1.0),
        extrude(outline(polyline([(41.5900269, 131.2033893), (51.6356579, 133.9428838), (51.6356579, 132.6479392), (45.0334023, 131.058689), (42.9953361, 130.5681797), (44.7979579, 130.0433347), (51.6356579, 128.0518668), (51.6356579, 126.1854788), (46.6790611, 124.7384763), (42.9953361, 123.6618084), (44.9745412, 123.1860143), (51.6356579, 121.5820488), (51.6356579, 120.2871042), (41.5900269, 123.0290513), (41.5900269, 124.3705943), (49.3400742, 126.7789951), (50.4216473, 127.114994), (49.119345, 127.4926862), (41.5900269, 129.6877154), (41.5900269, 131.2033893)])), frame((0.0, 571.0, 0.0), z_axis=(0.0, 1.0, 0.0), x_axis=(0.0, 0.0, 1.0)), (0.0, 0.0, 1.0), 1.0),
        extrude(outline(composite_curve([segment(trimmed(circle_curve(frame_2d((46.5900269, 134.0998468)), 8.0), [point((46.5900269, 126.0998468))], [point((46.5900269, 142.0998468))], False, "CARTESIAN"), True, "CONTINUOUS"), segment(trimmed(circle_curve(frame_2d((46.5900269, 134.0998468)), 8.0), [point((46.5900269, 142.0998468))], [point((46.5900269, 126.0998468))], False, "CARTESIAN"), True, "CONTINUOUS")], self_intersect=False)), frame((0.0, 541.0, 0.0), z_axis=(0.0, 1.0, 0.0), x_axis=(0.0, 0.0, 1.0)), (0.0, 0.0, 1.0), 30.0),
        extrude(outline(polyline([(118.1398187, -7.1235653), (128.1854497, -7.1235653), (128.1854497, -10.5890137), (128.0407495, -12.3818253), (127.3221533, -13.8582584), (125.6053707, -15.0477435), (123.2165903, -15.4426035), (121.1895605, -15.1752759), (119.7266164, -14.4885629), (118.8154953, -13.5713104), (118.311497, -12.3707889), (118.1398187, -10.7557869), (118.1398187, -7.1235653)]), holes=[polyline([(119.3955226, -8.3792692), (119.3955226, -10.6012765), (119.5770111, -12.2175047), (120.0895933, -13.1494724), (121.3367133, -13.9134407), (123.2362106, -14.1868996), (125.6151809, -13.6510182), (126.728637, -12.3474897), (126.9297459, -10.5669408), (126.9297459, -8.3792692), (119.3955226, -8.3792692)])]), frame((0.0, 571.0, 0.0), z_axis=(0.0, 1.0, 0.0), x_axis=(0.0, 0.0, 1.0)), (0.0, 0.0, 1.0), 1.0),
        extrude(outline(polyline([(121.5930044, -16.6983074), (121.5930044, -17.9540113), (120.3360742, -18.3586815), (119.5414491, -19.3470578), (119.2385596, -20.8529214), (119.4678727, -22.1650338), (120.0981772, -23.0123887), (120.940627, -23.2907528), (121.7242156, -23.0822863), (122.2944327, -22.2288001), (122.7739056, -20.4004265), (123.3931736, -18.4322579), (124.3275939, -17.3641738), (125.5759401, -17.0122334), (126.9971909, -17.4475604), (128.0002825, -18.7192058), (128.3424127, -20.5806887), (127.9843409, -22.5672515), (126.9321984, -23.8916267), (125.360116, -24.3894936), (125.360116, -23.1337898), (126.6501555, -22.4225512), (127.0867088, -20.6297397), (126.6550606, -18.832023), (125.6127283, -18.2679372), (124.7420743, -18.6677023), (124.0406459, -20.7180313), (123.4103414, -22.9400386), (122.3925346, -24.1552754), (120.9725101, -24.5464566), (119.4703253, -24.0964143), (118.3740369, -22.8014697), (117.9828557, -20.9019723), (118.4046938, -18.6591184), (119.6751129, -17.2403202), (121.5930044, -16.6983074)])), frame((0.0, 571.0, 0.0), z_axis=(0.0, 1.0, 0.0), x_axis=(0.0, 0.0, 1.0)), (0.0, 0.0, 1.0), 1.0),
        extrude(outline(composite_curve([segment(trimmed(circle_curve(frame_2d((126.8499756, -15.1501589)), 2.9851521), [point((126.8499756, -18.135311))], [point((126.8499756, -12.1650068))], False, "CARTESIAN"), True, "CONTINUOUS"), segment(trimmed(circle_curve(frame_2d((126.8499756, -15.1501589)), 2.9851521), [point((126.8499756, -12.1650068))], [point((126.8499756, -18.135311))], False, "CARTESIAN"), True, "CONTINUOUS")], self_intersect=False)), frame((0.0, 541.0, 0.0), z_axis=(0.0, 1.0, 0.0), x_axis=(0.0, 0.0, 1.0)), (0.0, 0.0, 1.0), 30.0),
        extrude(outline(composite_curve([segment(trimmed(circle_curve(frame_2d((117.0999756, -15.1501589)), 3.0), [point((117.0999756, -18.1501589))], [point((117.0999756, -12.1501589))], False, "CARTESIAN"), True, "CONTINUOUS"), segment(trimmed(circle_curve(frame_2d((117.0999756, -15.1501589)), 3.0), [point((117.0999756, -12.1501589))], [point((117.0999756, -18.1501589))], False, "CARTESIAN"), True, "CONTINUOUS")], self_intersect=False)), frame((0.0, 541.0, 0.0), z_axis=(0.0, 1.0, 0.0), x_axis=(0.0, 0.0, 1.0)), (0.0, 0.0, 1.0), 30.0),
        extrude(outline(composite_curve([segment(trimmed(circle_curve(frame_2d((107.3499443, -15.1501589)), 3.0), [point((107.3499443, -18.1501589))], [point((107.3499443, -12.1501589))], False, "CARTESIAN"), True, "CONTINUOUS"), segment(trimmed(circle_curve(frame_2d((107.3499443, -15.1501589)), 3.0), [point((107.3499443, -12.1501589))], [point((107.3499443, -18.1501589))], False, "CARTESIAN"), True, "CONTINUOUS")], self_intersect=False)), frame((0.0, 541.0, 0.0), z_axis=(0.0, 1.0, 0.0), x_axis=(0.0, 0.0, 1.0)), (0.0, 0.0, 1.0), 30.0),
        extrude(outline(composite_curve([segment(trimmed(circle_curve(frame_2d((136.5999756, -15.1501589)), 3.0), [point((136.5999756, -18.1501589))], [point((136.5999756, -12.1501589))], False, "CARTESIAN"), True, "CONTINUOUS"), segment(trimmed(circle_curve(frame_2d((136.5999756, -15.1501589)), 3.0), [point((136.5999756, -12.1501589))], [point((136.5999756, -18.1501589))], False, "CARTESIAN"), True, "CONTINUOUS")], self_intersect=False)), frame((0.0, 541.0, 0.0), z_axis=(0.0, 1.0, 0.0), x_axis=(0.0, 0.0, 1.0)), (0.0, 0.0, 1.0), 30.0),
        extrude(outline(polyline([(99.6239875, -5.6501594), (148.0, -5.6501594), (148.0, -24.1501589), (99.6239875, -24.1501589), (99.6239875, -5.6501594)]), holes=[polyline([(100.6239875, -6.6501594), (100.6239875, -23.1501589), (147.0, -23.1501589), (147.0, -6.6501594), (100.6239875, -6.6501594)])]), frame((0.0, 541.0, 0.0), z_axis=(0.0, 1.0, 0.0), x_axis=(0.0, 0.0, 1.0)), (0.0, 0.0, 1.0), 1.0),
        extrude(outline(polyline([(294.0108337, -153.1353281), (304.0564648, -153.1353281), (304.0564648, -156.6007765), (303.9117645, -158.3935881), (303.1931683, -159.8700212), (301.4763857, -161.0595063), (299.0876053, -161.4543663), (297.0605755, -161.1870387), (295.5976314, -160.5003256), (294.6865103, -159.5830732), (294.182512, -158.3825516), (294.0108337, -156.7675497), (294.0108337, -153.1353281)]), holes=[polyline([(295.2665376, -154.391032), (295.2665376, -156.6130392), (295.4480261, -158.2292675), (295.9606083, -159.1612352), (297.2077283, -159.9252035), (299.1072256, -160.1986624), (301.4861959, -159.662781), (302.5996521, -158.3592524), (302.8007609, -156.5787036), (302.8007609, -154.391032), (295.2665376, -154.391032)])]), frame((0.0, 585.0, 0.0), z_axis=(0.0, 1.0, 0.0), x_axis=(0.0, 0.0, 1.0)), (0.0, 0.0, 1.0), 1.0),
        extrude(outline(polyline([(297.4640194, -162.7100702), (297.4640194, -163.965774), (296.2070893, -164.3704442), (295.4124641, -165.3588205), (295.1095746, -166.8646842), (295.3388877, -168.1767966), (295.9691922, -169.0241515), (296.811642, -169.3025155), (297.5952306, -169.094049), (298.1654477, -168.2405628), (298.6449206, -166.4121893), (299.2641886, -164.4440206), (300.1986089, -163.3759366), (301.4469551, -163.0239961), (302.8682059, -163.4593232), (303.8712975, -164.7309686), (304.2134277, -166.5924515), (303.8553559, -168.5790143), (302.8032134, -169.9033894), (301.231131, -170.4012564), (301.231131, -169.1455525), (302.5211706, -168.434314), (302.9577239, -166.6415024), (302.5260757, -164.8437857), (301.4837433, -164.2797), (300.6130893, -164.6794651), (299.9116609, -166.7297941), (299.2813565, -168.9518013), (298.2635496, -170.1670382), (296.8435251, -170.5582194), (295.3413403, -170.1081771), (294.2450519, -168.8132325), (293.8538708, -166.9137351), (294.2757088, -164.6708812), (295.5461279, -163.252083), (297.4640194, -162.7100702)])), frame((0.0, 585.0, 0.0), z_axis=(0.0, 1.0, 0.0), x_axis=(0.0, 0.0, 1.0)), (0.0, 0.0, 1.0), 1.0),
        extrude(outline(composite_curve([segment(trimmed(circle_curve(frame_2d((299.0108337, -161.6898108)), 35.0), [point((299.0108337, -196.6898108))], [point((299.0108337, -126.6898108))], False, "CARTESIAN"), True, "CONTINUOUS"), segment(trimmed(circle_curve(frame_2d((299.0108337, -161.6898108)), 35.0), [point((299.0108337, -126.6898108))], [point((299.0108337, -196.6898108))], False, "CARTESIAN"), True, "CONTINUOUS")], self_intersect=False)), frame((0.0, 575.0, 0.0), z_axis=(0.0, 1.0, 0.0), x_axis=(0.0, 0.0, 1.0)), (0.0, 0.0, 1.0), 10.0),
        extrude(outline(polyline([(134.5999756, -252.738078), (144.6456066, -252.738078), (144.6456066, -256.4610438), (144.5499573, -257.9620023), (144.0802946, -259.1821442), (143.1090861, -259.9730905), (141.7393388, -260.2723012), (139.5688351, -259.4641871), (138.6810132, -256.5468829), (138.6810132, -253.9937818), (134.5999756, -253.9937818), (134.5999756, -252.738078)]), holes=[polyline([(139.9367171, -253.9937818), (139.9367171, -256.6204593), (140.3977958, -258.4696795), (141.695193, -259.0165974), (142.7350728, -258.6940875), (143.3040636, -257.8467326), (143.3899027, -256.5910287), (143.3899027, -253.9937818), (139.9367171, -253.9937818)])]), frame((0.0, 571.0, 0.0), z_axis=(0.0, 1.0, 0.0), x_axis=(0.0, 0.0, 1.0)), (0.0, 0.0, 1.0), 1.0),
        extrude(outline(polyline([(134.5999756, -260.8290293), (144.6456066, -264.8389431), (144.6456066, -265.9082534), (134.5999756, -269.9181671), (134.5999756, -268.5913394), (137.7392353, -267.441095), (137.7392353, -263.3036489), (134.5999756, -262.155857), (134.5999756, -260.8290293)]), holes=[polyline([(138.9949392, -263.7647276), (138.9949392, -266.9824688), (141.4646536, -266.0774791), (143.3899027, -265.3735982), (141.6804777, -264.7481988), (138.9949392, -263.7647276)])]), frame((0.0, 571.0, 0.0), z_axis=(0.0, 1.0, 0.0), x_axis=(0.0, 0.0, 1.0)), (0.0, 0.0, 1.0), 1.0),
        extrude(outline(composite_curve([segment(trimmed(circle_curve(frame_2d((139.5999756, -260.9001532)), 8.0), [point((139.5999756, -268.9001532))], [point((139.5999756, -252.9001532))], False, "CARTESIAN"), True, "CONTINUOUS"), segment(trimmed(circle_curve(frame_2d((139.5999756, -260.9001532)), 8.0), [point((139.5999756, -252.9001532))], [point((139.5999756, -268.9001532))], False, "CARTESIAN"), True, "CONTINUOUS")], self_intersect=False)), frame((0.0, 541.0, 0.0), z_axis=(0.0, 1.0, 0.0), x_axis=(0.0, 0.0, 1.0)), (0.0, 0.0, 1.0), 30.0),
        extrude(outline(composite_curve([segment(trimmed(circle_curve(frame_2d((99.6239875, 134.0998468)), 8.0), [point((99.6239875, 126.0998468))], [point((99.6239875, 142.0998468))], False, "CARTESIAN"), True, "CONTINUOUS"), segment(trimmed(circle_curve(frame_2d((99.6239875, 134.0998468)), 8.0), [point((99.6239875, 142.0998468))], [point((99.6239875, 126.0998468))], False, "CARTESIAN"), True, "CONTINUOUS")], self_intersect=False)), frame((0.0, 541.0, 0.0), z_axis=(0.0, 1.0, 0.0), x_axis=(0.0, 0.0, 1.0)), (0.0, 0.0, 1.0), 30.0),
        extrude(outline(composite_curve([segment(trimmed(circle_curve(frame_2d((76.0, 179.0)), 8.0), [point((76.0, 171.0))], [point((76.0, 187.0))], False, "CARTESIAN"), True, "CONTINUOUS"), segment(trimmed(circle_curve(frame_2d((76.0, 179.0)), 8.0), [point((76.0, 187.0))], [point((76.0, 171.0))], False, "CARTESIAN"), True, "CONTINUOUS")], self_intersect=False)), frame((0.0, 541.0, 0.0), z_axis=(0.0, 1.0, 0.0), x_axis=(0.0, 0.0, 1.0)), (0.0, 0.0, 1.0), 30.0),
        extrude(outline(polyline([(-246.8707486, 541.0), (-246.8707486, 505.0), (-294.0966381, 505.0), (-294.0966381, 541.0), (-246.8707486, 541.0)])), origin_with_axes(), (0.0, 0.0, 1.0), 4.2000122),
        extrude(outline(polyline([(246.8707486, 541.0), (294.0966381, 541.0), (294.0966381, 505.0), (246.8707486, 505.0), (246.8707486, 541.0)])), origin_with_axes(), (0.0, 0.0, 1.0), 4.2000122),
        extrude(outline(composite_curve([segment(trimmed(circle_curve(frame_2d((-269.0, 35.0)), 16.477447), [point((-285.477447, 35.0))], [point((-252.522553, 35.0))], False, "CARTESIAN"), True, "CONTINUOUS"), segment(trimmed(circle_curve(frame_2d((-269.0, 35.0)), 16.477447), [point((-252.522553, 35.0))], [point((-285.477447, 35.0))], False, "CARTESIAN"), True, "CONTINUOUS")], self_intersect=False)), origin_with_axes(), (0.0, 0.0, 1.0), 4.2000122),
        extrude(outline(composite_curve([segment(trimmed(circle_curve(frame_2d((269.0, 35.0)), 16.477447), [point((252.522553, 35.0))], [point((285.477447, 35.0))], False, "CARTESIAN"), True, "CONTINUOUS"), segment(trimmed(circle_curve(frame_2d((269.0, 35.0)), 16.477447), [point((285.477447, 35.0))], [point((252.522553, 35.0))], False, "CARTESIAN"), True, "CONTINUOUS")], self_intersect=False)), origin_with_axes(), (0.0, 0.0, 1.0), 4.2000122),
    ])


if __name__ == "__main__":
    model = new_model("IFC4")
    model_context = context("Model", 3, world=origin())
    ifc_project = project(units=[si_unit("LENGTHUNIT", "METRE", prefix="MILLI")], contexts=[model_context])
    site = spatial("IfcSite", under=ifc_project)
    building = spatial("IfcBuilding", under=site)
    placement = place(None, origin())
    specialty_equipment_shape = specialty_equipment_f63f0287(model_context)
    element("IfcBuildingElementProxy", 1, Name="Specialty Equipment", at=placement, inside=building, context=model_context, shape_type="MappedRepresentation", body=[
        mapped(specialty_equipment_shape, transform((0.0, 0.0, 0.0), x_axis=(1.0, 0.0, 0.0), y_axis=(0.0, 1.0, 0.0), z_axis=(0.0, 0.0, 1.0))),
    ])
    save(model, "model.ifc")
